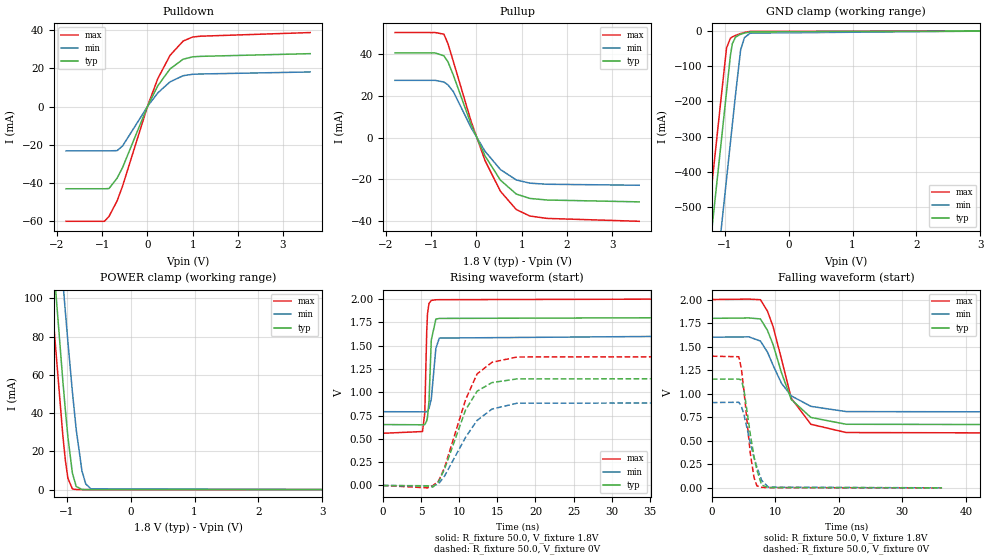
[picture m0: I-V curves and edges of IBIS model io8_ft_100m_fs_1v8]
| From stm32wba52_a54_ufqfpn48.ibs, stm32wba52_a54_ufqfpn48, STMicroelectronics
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[Model]   io8_ft_100m_fs_1v8
Model_type I/O
Polarity   Non-Inverting
Enable   Active-Low
| CAP_THRESHOLD on pad IOFT is "UDTCAPC" :
| Rising=30.0% of vddiom   Falling=70.0% of vddiom
| C_comp min and max val. don't necessarily correlate with the min and max pvt
| but are the smallest and greatest pad capacitance found.
| var   typ   min   max
C_comp   2.20755pF  2.09930pF  2.39591pF
|C_comp_pullup   1.38185pF  1.31775pF  1.46417pF
|C_comp_pulldown   825.70019fF  781.55002fF  931.74609fF
Vinl = 800.0mV
Vinh = 1.0V
Vmeas = 900.0mV   | Reference voltage for timing measurements
Cref  = 50.0pF   | Timing specification test load capacitance value
Rref  = 1.0MOhm   | Timing specification test load resistance value
Vref  = 990.0mV   | Timing specification test load voltage
[Model Spec]
| TIME_THRESHOLD on pin ZIV11 is "CMOS" :
| Rising=50.0% of vdd   Falling=50.0% of vdd
Vinl 702.50000mV 642.50000mV 771.50000mV
Vinh 1.09050V 944.50000mV 1.21950V
| variable   typ   min   max
[Temperature Range] 25.0 140.0 -40.0
| variable   typ   min   max
[Voltage Range] 1.8V 1.6V 2.0V
| variable   typ   min   max
[POWER Clamp Reference] 1.8V 1.6V 2.0V
| variable   typ   min   max
[GND Clamp Reference] 0V 0V 0V
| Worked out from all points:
|   slope of the pulldown table from 0 to 0.27 V, typ, clamps not added: 21.7 ohm
|   slope of the pullup table from 0 to 0.27 V, typ, clamps not added: 22.5 ohm
|   GND clamp passes 1 mA (typ) near -0.51 V on its own axis
|   POWER clamp passes 1 mA (typ) near -0.83 V on its own axis
|   rising waveform, R_fixture 50.0, V_fixture 1.8V: 20-80 % time 322ps typ, 505ps min, 248ps max; typ from 0.654 V to 1.8 V
|   falling waveform, R_fixture 50.0, V_fixture 1.8V: 20-80 % time 4.02ns typ, 4.38ns min, 4.02ns max; typ from 1.8 V to 0.654 V
|   rising waveform, R_fixture 50.0, V_fixture 0V: 20-80 % time 3.25ns typ, 4ns min, 3.39ns max; typ from 0 V to 1.16 V
|   falling waveform, R_fixture 50.0, V_fixture 0V: 20-80 % time 1.6ns typ, 2.02ns min, 1.33ns max; typ from 1.16 V to 0 V
[POWER Clamp]
-1.8V     396.4mA    438.1mA    365.5mA
-1.26V    143.5mA    194.6mA    112.6mA
-1.19V    112.3mA    164.2mA    81.56mA
-1.06V    57.23mA    109.3mA    28.68mA
-1.02V    41.75mA    93.06mA    15.5mA
-980mV    27.6mA     77.28mA    5.935mA
-910mV    8.693mA    51.24mA    382.3uA
-850mV    1.642mA    31.41mA    23.97uA
-760mV    69.41uA    9.714mA    358.6nA
-700mV    7.83uA     2.919mA    21.79nA
-620mV    424.6nA    410.3uA    573.9pA
3.6V      0A         0A         0A
[GND Clamp]
-1.8V     -1.583A    -1.83A     -1.456A
-1.43V    -953.9mA   -1.201A    -826.8mA
-1.24V    -630.9mA   -877.8mA   -503.8mA
-1.05V    -307.9mA   -554.8mA   -180.8mA
-970mV    -171.9mA   -418.8mA   -48.31mA
-910mV    -69.87mA   -316.8mA   -20.91mA
-880mV    -36.5mA    -265.8mA   -17.19mA
-830mV    -17.68mA   -180.8mA   -12.97mA
-750mV    -9.66mA    -53.66mA   -7.697mA
-690mV    -6.479mA   -19.19mA   -4.622mA
-600mV    -3.058mA   -6.478mA   -1.59mA
3.6V      1.281nA    1.39uA     517.2pA
| variable   typ   min   max
[Pullup Reference] 1.8V 1.6V 2.0V
| variable   typ   min   max
[Pulldown Reference] 0V 0V 0V
[Pullup]
-1.8V     40.39mA    27.3mA     50.13mA
-910mV    40.38mA    27.3mA     50.13mA
-720mV    39.03mA    26.51mA    49.35mA
-630mV    36.17mA    25.17mA    44.85mA
-510mV    29.75mA    21.9mA     36.26mA
-120mV    6.338mA    4.782mA    7.854mA
190mV     -8.788mA   -6.58mA    -11.01mA
530mV     -20.35mA   -15.28mA   -25.66mA
880mV     -26.99mA   -20.26mA   -34.39mA
1.18V     -29.09mA   -21.8mA    -37.49mA
1.56V     -29.85mA   -22.32mA   -38.64mA
3.6V      -30.74mA   -22.8mA    -40.02mA
[Pulldown]
-1.8V     -42.97mA   -23.15mA   -59.99mA
-950mV    -42.97mA   -23.15mA   -59.99mA
-850mV    -42.87mA   -23.15mA   -57.45mA
-670mV    -37.41mA   -23.03mA   -49.3mA
-550mV    -31.91mA   -20.61mA   -41.6mA
10mV      539.8uA    356.7uA    722uA
230mV     10.88mA    7.174mA    14.64mA
500mV     19.69mA    12.93mA    26.79mA
790mV     24.78mA    16.15mA    34.26mA
1V        26.02mA    16.89mA    36.38mA
1.18V     26.27mA    17.05mA    36.82mA
3.6V      27.68mA    18.11mA    38.71mA
[Ramp]
dV/dt_r 693.11066mV/3.20118ns 543.26724mV/3.98947ns 838.84424mV/3.36461ns
dV/dt_f 687.69285mV/3.59146ns 484.94098mV/4.15996ns 864.00255mV/3.42462ns
R_load = 50.0
| Removed startup time: 0s 0s 0s  .
| Removed end time: 36.25ns.
[Rising Waveform]
R_fixture   = 50.0
V_fixture   = 1.8V
V_fixture_min = 1.6V
V_fixture_max = 2.0V
0s        653.8mV    791.8mV    560mV
5.2ns     651.3mV    790.6mV    578.8mV
5.5ns     653.3mV    788.1mV    782.7mV
5.75ns    694.7mV    792.7mV    1.649V
5.85ns    732.3mV    799.4mV    1.84V
6.05ns    902.5mV    827.7mV    1.955V
6.35ns    1.561V     928.2mV    1.986V
6.95ns    1.785V     1.472V     1.993V
7.4ns     1.793V     1.582V     1.994V
36.25ns   1.8V       1.6V       2V
| Removed startup time: 0s 0s 0s  .
| Removed end time: 199.25ns.
[Falling Waveform]
R_fixture   = 50.0
V_fixture   = 1.8V
V_fixture_min = 1.6V
V_fixture_max = 2.0V
0s        1.8V       1.6V       2V
5.85ns    1.804V     1.603V     2.004V
7.65ns    1.794V     1.559V     1.998V
8.75ns    1.673V     1.442V     1.877V
9.65ns    1.52V      1.3V       1.711V
10.95ns   1.226V     1.112V     1.371V
12.5ns    938.3mV    976.9mV    951.9mV
15.6ns    747.6mV    865.3mV    675.1mV
21.15ns   675.3mV    809.9mV    587.4mV
199.3ns   653.8mV    791.8mV    560mV
| Removed startup time: 0s 0s 0s  .
| Removed end time: 199.2ns.
[Rising Waveform]
R_fixture   = 50.0
V_fixture   = 0V
V_fixture_min = 0V
V_fixture_max = 0V
0s        4.66nV     680.4nV    3.931nV
5.85ns    -5.875mV   -3.215mV   -25.64mV
6.55ns    -17.15mV   -6.295mV   -1.316mV
7.3ns     38.79mV    16.25mV    47.78mV
8.1ns     178.5mV    103.1mV    195.2mV
10.85ns   812.2mV    518.2mV    922.4mV
12.35ns   1.012V     698.2mV    1.197V
14.3ns    1.104V     820mV      1.322V
17.6ns    1.144V     882.9mV    1.379V
199.2ns   1.155V     905.4mV    1.398V
| Removed startup time: 0s 0s 0s  .
| Removed end time: 36.25ns.
[Falling Waveform]
R_fixture   = 50.0
V_fixture   = 0V
V_fixture_min = 0V
V_fixture_max = 0V
0s        1.155V     905.5mV    1.398V
4.25ns    1.155V     908.9mV    1.392V
4.65ns    1.145V     864.5mV    1.265V
5.05ns    1.041V     780.1mV    1.032V
6.05ns    570.6mV    478.5mV    367.9mV
6.65ns    326.2mV    317.5mV    106.3mV
7.1ns     189.9mV    219mV      21.24mV
7.85ns    29.74mV    78.62mV    5.408mV
8.9ns     3.144mV    7.692mV    2.549mV
36.25ns   741.1nV    624.9nV    2.265uV
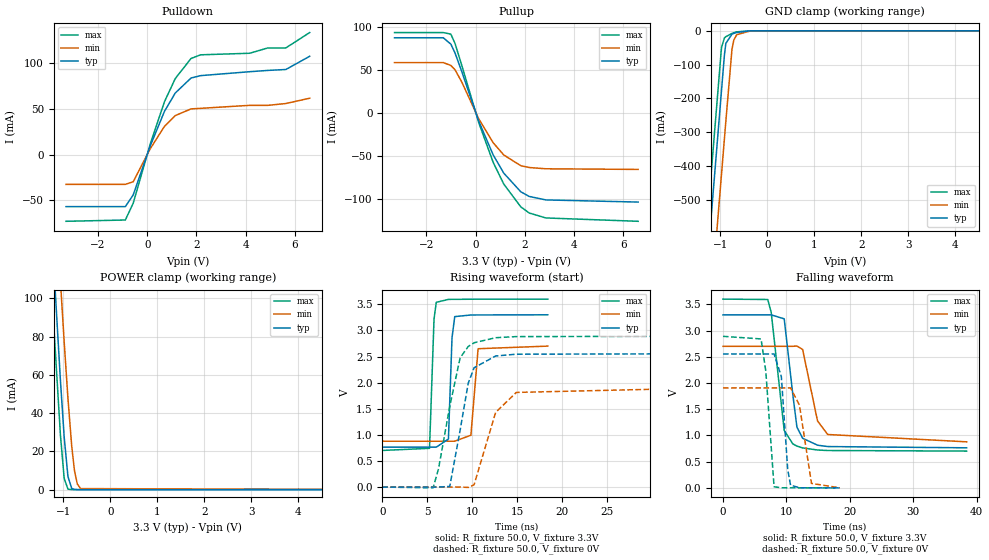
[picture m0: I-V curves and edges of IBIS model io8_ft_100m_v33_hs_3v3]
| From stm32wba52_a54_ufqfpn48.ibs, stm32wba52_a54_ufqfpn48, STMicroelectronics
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[Model]   io8_ft_100m_v33_hs_3v3
Model_type I/O
Polarity   Non-Inverting
Enable   Active-Low
| CAP_THRESHOLD on pad IOFT is "UDTCAPC" :
| Rising=30.0% of vddiom   Falling=70.0% of vddiom
| C_comp min and max val. don't necessarily correlate with the min and max pvt
| but are the smallest and greatest pad capacitance found.
| var   typ   min   max
C_comp   2.72379pF  2.64035pF  2.77560pF
|C_comp_pullup   1.81482pF  1.75600pF  1.84990pF
|C_comp_pulldown   908.97285fF  884.35130fF  925.69520fF
Vinl = 1.35V
Vinh = 1.8V
Vmeas = 1.65V   | Reference voltage for timing measurements
Cref  = 50.0pF   | Timing specification test load capacitance value
Rref  = 1.0MOhm   | Timing specification test load resistance value
Vref  = 1.815V   | Timing specification test load voltage
[Model Spec]
| TIME_THRESHOLD on pin ZIV33M is "CMOS" :
| Rising=50.0% of vddiom   Falling=50.0% of vddiom
Vinl 1.28450V 1.07650V 1.38450V
Vinh 1.79550V 1.49050V 1.94250V
| variable   typ   min   max
[Temperature Range] 25.0 140.0 -40.0
| variable   typ   min   max
[Voltage Range] 3.3V 2.7V 3.6V
| variable   typ   min   max
[POWER Clamp Reference] 3.3V 2.7V 3.6V
| variable   typ   min   max
[GND Clamp Reference] 0V 0V 0V
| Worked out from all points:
|   slope of the pulldown table from 0 to 0.495 V, typ, clamps not added: 14 ohm
|   slope of the pullup table from 0 to 0.495 V, typ, clamps not added: 13.8 ohm
|   GND clamp passes 1 mA (typ) near -0.51 V on its own axis
|   POWER clamp passes 1 mA (typ) near -0.83 V on its own axis
|   rising waveform, R_fixture 50.0, V_fixture 3.3V: 20-80 % time 262ps typ, 340ps min, 238ps max; typ from 0.764 V to 3.3 V
|   falling waveform, R_fixture 50.0, V_fixture 3.3V: 20-80 % time 1.18ns typ, 1.6ns min, 1.55ns max; typ from 3.3 V to 0.764 V
|   rising waveform, R_fixture 50.0, V_fixture 0V: 20-80 % time 1.51ns typ, 2.09ns min, 1.86ns max; typ from 0 V to 2.55 V
|   falling waveform, R_fixture 50.0, V_fixture 0V: 20-80 % time 833ps typ, 1.11ns min, 843ps max; typ from 2.55 V to 0 V
[POWER Clamp]
-3.3V     1.123A     1.139A     1.091A
-1.36V    189.2mA    238.8mA    158.1mA
-1.25V    139mA      190.3mA    108.1mA
-1.18V    107.9mA    159.9mA    77.22mA
-1.06V    57.23mA    109.3mA    28.68mA
-980mV    27.6mA     77.28mA    5.935mA
-900mV    6.895mA    47.74mA    242.8uA
-820mV    594.6uA    22.85mA    5.912uA
-760mV    69.41uA    9.714mA    358.6nA
-700mV    7.83uA     2.919mA    21.86nA
-630mV    611.5nA    529.9uA    954.5pA
6.6V      0A         0A         0A
[GND Clamp]
-3.3V     -4.134A    -4.382A    -4.006A
-1.59V    -1.227A    -1.475A    -1.099A
-1.25V    -648.9mA   -896.7mA   -520.9mA
-980mV    -189.9mA   -437.7mA   -61.92mA
-970mV    -172.9mA   -420.7mA   -48.45mA
-910mV    -70.86mA   -318.7mA   -21.03mA
-880mV    -37.23mA   -267.7mA   -17.31mA
-750mV    -9.908mA   -55.25mA   -7.768mA
-710mV    -7.626mA   -27.41mA   -5.608mA
-650mV    -4.885mA   -11.6mA    -3.058mA
-360mV    -31.22uA   -443.6uA   -1.188uA
6.6V      2.31nA     2.655uA    974.6pA
| variable   typ   min   max
[Pullup Reference] 3.3V 2.7V 3.6V
| variable   typ   min   max
[Pulldown Reference] 0V 0V 0V
[Pullup]
-3.3V     87.4mA     58.48mA    93.44mA
-1.32V    87.4mA     58.48mA    93.44mA
-1.01V    79.96mA    55.17mA    91.59mA
-840mV    69.65mA    50.07mA    80.67mA
-570mV    48.3mA     36.04mA    55.62mA
120mV     -9.566mA   -6.929mA   -11.25mA
710mV     -49.08mA   -34.92mA   -57.81mA
1.14V     -70.33mA   -49.14mA   -83.06mA
1.83V     -91.98mA   -61.62mA   -109.5mA
2.17V     -97.42mA   -63.75mA   -116.7mA
2.85V     -101.5mA   -65.23mA   -122.5mA
6.6V      -104mA     -65.97mA   -126.4mA
[Pulldown]
-3.3V     -56.7mA    -32.4mA    -72.73mA
-890mV    -56.7mA    -32.4mA    -71.32mA
-570mV    -43.94mA   -29.54mA   -52.99mA
120mV     9.474mA    6.407mA    11.48mA
700mV     47.33mA    30.97mA    57.88mA
1.14V     67.41mA    42.74mA    83.2mA
1.78V     83.75mA    50.04mA    105.1mA
2.17V     86.37mA    50.65mA    109.1mA
4.16V     90.65mA    53.91mA    110.8mA
4.9V      92.06mA    53.91mA    116.6mA
5.63V     93.04mA    55.89mA    116.6mA
6.6V      107.5mA    61.71mA    133.4mA
[Ramp]
dV/dt_r 1.53258V/1.50294ns 1.14345V/2.03091ns 1.73411V/1.84246ns
dV/dt_f 1.52158V/1.17992ns 1.09316V/1.53118ns 1.73924V/1.55401ns
R_load = 50.0
| Removed startup time: 0s 0s 0s  .
| Removed end time: 18.4ns.
[Rising Waveform]
R_fixture   = 50.0
V_fixture   = 3.3V
V_fixture_min = 2.7V
V_fixture_max = 3.6V
0s        764mV      878.1mV    701.3mV
5.25ns    764.1mV    878.1mV    742.1mV
5.75ns    764.1mV    878.1mV    3.217V
6ns       764.1mV    878.1mV    3.539V
7.35ns    919.8mV    878.1mV    3.595V
7.75ns    2.86V      878.1mV    3.596V
8.05ns    3.265V     878.1mV    3.596V
9.85ns    3.296V     992.7mV    3.598V
10.65ns   3.297V     2.65V      3.599V
18.4ns    3.3V       2.7V       3.6V
| Removed startup time: 0s 0s 0s  .
| Removed end time: 38.4ns.
[Falling Waveform]
R_fixture   = 50.0
V_fixture   = 3.3V
V_fixture_min = 2.7V
V_fixture_max = 3.6V
0s        3.3V       2.7V       3.6V
7.05ns    3.3V       2.7V       3.593V
7.6ns     3.3V       2.7V       3.347V
9.65ns    3.224V     2.7V       1.096V
11ns      1.785V     2.7V       839.4mV
11.65ns   1.16V      2.706V     796.8mV
12.55ns   946.5mV    2.641V     762mV
14.9ns    814mV      1.276V     722.2mV
16.5ns    788mV      1.018V     712.6mV
38.4ns    764mV      878.1mV    701.3mV
| Removed startup time: 0s 0s 0s  .
| Removed end time: 38.35ns.
[Rising Waveform]
R_fixture   = 50.0
V_fixture   = 0V
V_fixture_min = 0V
V_fixture_max = 0V
0s        20.88nV    574.1nV    33.14nV
5.65ns    5.625uV    585.7nV    -15.38mV
6.25ns    9.505uV    653.9nV    349.3mV
7.5ns     12.34mV    2.897uV    1.546V
8.65ns    1.088V     46.07uV    2.476V
9.55ns    1.988V     -7.138mV   2.692V
10.2ns    2.285V     42.2mV     2.764V
12.6ns    2.511V     1.431V     2.861V
14.9ns    2.545V     1.813V     2.882V
38.35ns   2.554V     1.906V     2.89V
| Removed startup time: 0s 0s 0s  .
| Removed end time: 18.4ns.
[Falling Waveform]
R_fixture   = 50.0
V_fixture   = 0V
V_fixture_min = 0V
V_fixture_max = 0V
0s        2.554V     1.906V     2.89V
6ns       2.554V     1.906V     2.841V
6.75ns    2.554V     1.906V     2.224V
8.05ns    2.554V     1.906V     20.75mV
9.2ns     2.12V      1.906V     2.078mV
10.2ns    350.4mV    1.906V     1.317mV
10.65ns   51.1mV     1.906V     1.141mV
12.05ns   2.086mV    1.578V     815.6uV
13.95ns   1.02mV     84.68mV    515.9uV
18.4ns    291.9uV    1.262mV    146.9uV
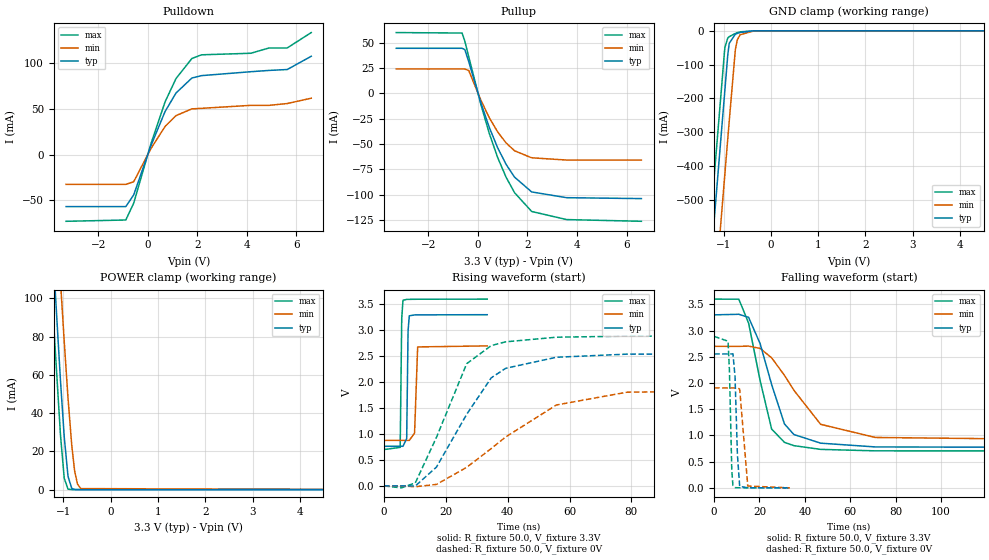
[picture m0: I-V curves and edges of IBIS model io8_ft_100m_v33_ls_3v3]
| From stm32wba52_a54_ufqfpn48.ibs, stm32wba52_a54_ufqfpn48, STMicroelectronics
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[Model]   io8_ft_100m_v33_ls_3v3
Model_type I/O
Polarity   Non-Inverting
Enable   Active-Low
| CAP_THRESHOLD on pad IOFT is "UDTCAPC" :
| Rising=30.0% of vddiom   Falling=70.0% of vddiom
| C_comp min and max val. don't necessarily correlate with the min and max pvt
| but are the smallest and greatest pad capacitance found.
| var   typ   min   max
C_comp   2.72379pF  2.64023pF  2.77562pF
|C_comp_pullup   1.81413pF  1.75530pF  1.84922pF
|C_comp_pulldown   909.66885fF  884.92580fF  926.39520fF
Vinl = 1.35V
Vinh = 1.8V
Vmeas = 1.65V   | Reference voltage for timing measurements
Cref  = 50.0pF   | Timing specification test load capacitance value
Rref  = 1.0MOhm   | Timing specification test load resistance value
Vref  = 1.815V   | Timing specification test load voltage
[Model Spec]
| TIME_THRESHOLD on pin ZIV33M is "CMOS" :
| Rising=50.0% of vddiom   Falling=50.0% of vddiom
Vinl 1.28450V 1.07650V 1.38450V
Vinh 1.79550V 1.49050V 1.94250V
| variable   typ   min   max
[Temperature Range] 25.0 140.0 -40.0
| variable   typ   min   max
[Voltage Range] 3.3V 2.7V 3.6V
| variable   typ   min   max
[POWER Clamp Reference] 3.3V 2.7V 3.6V
| variable   typ   min   max
[GND Clamp Reference] 0V 0V 0V
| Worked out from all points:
|   slope of the pulldown table from 0 to 0.495 V, typ, clamps not added: 14 ohm
|   slope of the pullup table from 0 to 0.495 V, typ, clamps not added: 13.8 ohm
|   GND clamp passes 1 mA (typ) near -0.51 V on its own axis
|   POWER clamp passes 1 mA (typ) near -0.83 V on its own axis
|   rising waveform, R_fixture 50.0, V_fixture 3.3V: 20-80 % time 263ps typ, 346ps min, 236ps max; typ from 0.764 V to 3.3 V
|   falling waveform, R_fixture 50.0, V_fixture 3.3V: 20-80 % time 10.5ns typ, 17.9ns min, 8.53ns max; typ from 3.3 V to 0.764 V
|   rising waveform, R_fixture 50.0, V_fixture 0V: 20-80 % time 15.6ns typ, 27.2ns min, 11.8ns max; typ from 0 V to 2.55 V
|   falling waveform, R_fixture 50.0, V_fixture 0V: 20-80 % time 1.1ns typ, 1.6ns min, 919ps max; typ from 2.55 V to 0 V
[POWER Clamp]
-3.3V     1.123A     1.139A     1.091A
-1.36V    189.2mA    238.8mA    158.1mA
-1.25V    139mA      190.3mA    108.1mA
-1.18V    107.9mA    159.9mA    77.22mA
-1.06V    57.23mA    109.3mA    28.68mA
-980mV    27.6mA     77.28mA    5.935mA
-900mV    6.895mA    47.74mA    242.8uA
-820mV    594.6uA    22.85mA    5.912uA
-760mV    69.41uA    9.714mA    358.6nA
-700mV    7.83uA     2.919mA    21.86nA
-630mV    611.5nA    529.9uA    954.5pA
6.6V      0A         0A         0A
[GND Clamp]
-3.3V     -4.134A    -4.382A    -4.006A
-1.59V    -1.227A    -1.475A    -1.099A
-1.25V    -648.9mA   -896.7mA   -520.9mA
-980mV    -189.9mA   -437.7mA   -61.92mA
-970mV    -172.9mA   -420.7mA   -48.45mA
-910mV    -70.86mA   -318.7mA   -21.03mA
-880mV    -37.23mA   -267.7mA   -17.31mA
-750mV    -9.908mA   -55.25mA   -7.768mA
-710mV    -7.626mA   -27.41mA   -5.608mA
-650mV    -4.885mA   -11.6mA    -3.058mA
-360mV    -31.22uA   -443.6uA   -1.188uA
6.6V      2.31nA     2.655uA    974.6pA
| variable   typ   min   max
[Pullup Reference] 3.3V 2.7V 3.6V
| variable   typ   min   max
[Pulldown Reference] 0V 0V 0V
[Pullup]
-3.3V     44.29mA    23.88mA    59.81mA
-640mV    44.29mA    23.88mA    59.35mA
-530mV    42.99mA    23.88mA    51.44mA
-370mV    31.03mA    22.28mA    35.9mA
120mV     -9.566mA   -6.929mA   -11.25mA
460mV     -33.84mA   -24.28mA   -39.82mA
800mV     -54.04mA   -38.32mA   -63.68mA
1.14V     -70.33mA   -49.14mA   -83.06mA
1.48V     -82.86mA   -56.83mA   -98.19mA
2.17V     -97.42mA   -63.75mA   -116.7mA
3.58V     -103.1mA   -65.97mA   -124.7mA
6.6V      -104mA     -65.97mA   -126.4mA
[Pulldown]
-3.3V     -56.7mA    -32.4mA    -72.73mA
-890mV    -56.7mA    -32.4mA    -71.32mA
-570mV    -43.94mA   -29.54mA   -52.99mA
120mV     9.474mA    6.407mA    11.48mA
700mV     47.33mA    30.97mA    57.88mA
1.14V     67.41mA    42.74mA    83.2mA
1.78V     83.75mA    50.04mA    105.1mA
2.17V     86.37mA    50.65mA    109.1mA
4.16V     90.65mA    53.91mA    110.8mA
4.9V      92.06mA    53.91mA    116.6mA
5.63V     93.04mA    55.89mA    116.6mA
6.6V      107.5mA    61.71mA    133.4mA
[Ramp]
dV/dt_r 1.53259V/15.47369ns 1.14354V/27.02731ns 1.73412V/11.7418ns
dV/dt_f 1.52158V/10.47709ns 1.09315V/17.89446ns 1.73923V/8.40245ns
R_load = 50.0
| Removed startup time: 0s 0s 0s  .
| Removed end time: 33.4ns.
[Rising Waveform]
R_fixture   = 50.0
V_fixture   = 3.3V
V_fixture_min = 2.7V
V_fixture_max = 3.6V
0s        764mV      878.1mV    701.3mV
5.25ns    764.1mV    878.1mV    743.4mV
5.75ns    764.1mV    878.1mV    3.226V
6.15ns    764.1mV    878.1mV    3.578V
7.35ns    913.1mV    878.1mV    3.595V
7.8ns     2.992V     878.1mV    3.596V
8.2ns     3.278V     878.1mV    3.596V
9.9ns     3.296V     1.019V     3.597V
10.9ns    3.297V     2.679V     3.598V
33.4ns    3.3V       2.699V     3.6V
| Removed startup time: 0s 0s 0s  .
| Removed end time: 248.4ns.
[Falling Waveform]
R_fixture   = 50.0
V_fixture   = 3.3V
V_fixture_min = 2.7V
V_fixture_max = 3.6V
0s        3.3V       2.7V       3.6V
10.9ns    3.311V     2.699V     3.599V
15.2ns    3.253V     2.704V     3.145V
20.3ns    2.75V      2.659V     2.044V
25.35ns   1.972V     2.481V     1.122V
31ns      1.22V      2.147V     868.6mV
35.15ns   1.018V     1.863V     805.4mV
46.95ns   852.6mV    1.212V     734.1mV
71ns      780.8mV    961.5mV    706.1mV
248.4ns   764mV      878.1mV    701.3mV
| Removed startup time: 0s 0s 0s  .
| Removed end time: 248.4ns.
[Rising Waveform]
R_fixture   = 50.0
V_fixture   = 0V
V_fixture_min = 0V
V_fixture_max = 0V
0s        20.88nV    574.1nV    33.14nV
5.7ns     7.251uV    588.2nV    -36.76mV
10.15ns   -751.1uV   -14.51mV   59.89mV
17ns      365.1mV    29.91mV    939.3mV
26.75ns   1.38V      358.8mV    2.356V
34.7ns    2.084V     721.4mV    2.705V
39.35ns   2.267V     943.9mV    2.777V
55.75ns   2.48V      1.56V      2.866V
78.6ns    2.54V      1.807V     2.887V
248.4ns   2.554V     1.906V     2.89V
| Removed startup time: 0s 0s 0s  .
| Removed end time: 33.4ns.
[Falling Waveform]
R_fixture   = 50.0
V_fixture   = 0V
V_fixture_min = 0V
V_fixture_max = 0V
0s        2.554V     1.906V     2.89V
6.15ns    2.554V     1.906V     2.797V
6.775ns   2.554V     1.906V     2.229V
7.8ns     2.554V     1.906V     340.3mV
8.3ns     2.558V     1.906V     46.13mV
9.225ns   2.132V     1.906V     4.788mV
10.28ns   636.9mV    1.906V     2.555mV
11.28ns   29.05mV    1.886V     2.112mV
14.85ns   1.782mV    34.65mV    1.452mV
33.4ns    226.8uV    363uV      160.2uV
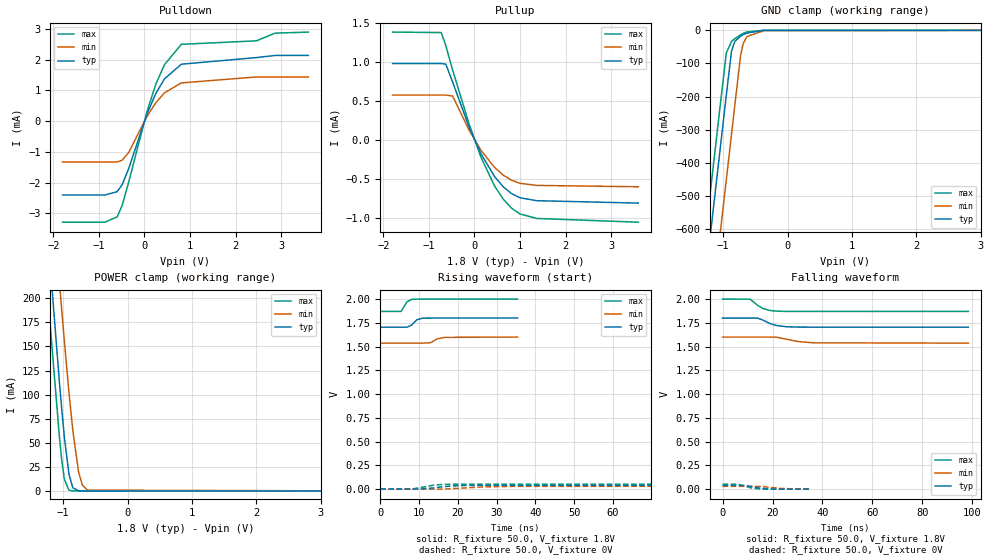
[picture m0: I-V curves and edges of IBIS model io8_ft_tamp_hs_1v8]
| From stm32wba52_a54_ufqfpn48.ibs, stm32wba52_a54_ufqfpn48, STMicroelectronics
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[Model]   io8_ft_tamp_hs_1v8
Model_type I/O
Polarity   Non-Inverting
Enable   Active-Low
| CAP_THRESHOLD on pad IOFT is "UDTCAPC" :
| Rising=30.0% of vddiom   Falling=70.0% of vddiom
| C_comp min and max val. don't necessarily correlate with the min and max pvt
| but are the smallest and greatest pad capacitance found.
| var   typ   min   max
C_comp   6.29605pF  5.93294pF  7.05009pF
|C_comp_pullup   4.08842pF  3.87382pF  4.47715pF
|C_comp_pulldown   2.20764pF  2.05912pF  2.57293pF
Vinl = 800.0mV
Vinh = 1.0V
Vmeas = 900.0mV   | Reference voltage for timing measurements
Cref  = 50.0pF   | Timing specification test load capacitance value
Rref  = 1.0MOhm   | Timing specification test load resistance value
Vref  = 990.0mV   | Timing specification test load voltage
[Model Spec]
| TIME_THRESHOLD on pin ZIV33SW is "CMOS" :
| Rising=50.0% of VDDV33SW   Falling=50.0% of VDDV33SW
Vinl 697.50000mV 636.50000mV 765.50000mV
Vinh 1.08850V 942.50000mV 1.21750V
| variable   typ   min   max
[Temperature Range] 25.0 140.0 -40.0
| variable   typ   min   max
[Voltage Range] 1.8V 1.6V 2.0V
| variable   typ   min   max
[POWER Clamp Reference] 1.8V 1.6V 2.0V
| variable   typ   min   max
[GND Clamp Reference] 0V 0V 0V
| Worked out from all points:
|   slope of the pulldown table from 0 to 0.27 V, typ, clamps not added: 283 ohm
|   slope of the pullup table from 0 to 0.27 V, typ, clamps not added: 855 ohm
|   GND clamp passes 1 mA (typ) near -0.47 V on its own axis
|   POWER clamp passes 1 mA (typ) near -0.81 V on its own axis
|   rising waveform, R_fixture 50.0, V_fixture 1.8V: 20-80 % time 1.33ns typ, 1.84ns min, 1.13ns max; typ from 1.7 V to 1.8 V
|   falling waveform, R_fixture 50.0, V_fixture 1.8V: 20-80 % time 5.31ns typ, 7.46ns min, 4.31ns max; typ from 1.8 V to 1.7 V
[POWER Clamp]
-1.8V     792.8mA    876.2mA    731mA
-1.26V    287mA      389.3mA    225.1mA
-1.19V    224.6mA    328.4mA    163.1mA
-1.06V    114.5mA    218.6mA    57.35mA
-1.02V    83.5mA     186.1mA    30.99mA
-980mV    55.21mA    154.6mA    11.87mA
-910mV    17.39mA    102.5mA    764.6uA
-850mV    3.285mA    62.83mA    47.95uA
-760mV    138.8uA    19.43mA    717.2nA
-700mV    15.66uA    5.838mA    43.61nA
-620mV    848.9nA    820.4uA    1.186nA
3.6V      0A         0A         0A
[GND Clamp]
-1.8V     -1.639A    -1.894A    -1.509A
-1.43V    -1.01A     -1.265A    -879.6mA
-1.24V    -686.9mA   -942.2mA   -556.6mA
-1.05V    -363.9mA   -619.2mA   -233.6mA
-950mV    -193.9mA   -449.2mA   -67.62mA
-870mV    -63.28mA   -313.2mA   -33.62mA
-820mV    -33.62mA   -228.2mA   -25.22mA
-730mV    -17.72mA   -77.21mA   -13.43mA
-690mV    -13.46mA   -40.36mA   -9.392mA
-630mV    -8.329mA   -18.75mA   -4.815mA
-370mV    -86.03uA   -1.078mA   -3.689uA
3.6V      2.71nA     3.15uA     1.142nA
| variable   typ   min   max
[Pullup Reference] 1.8V 1.6V 2.0V
| variable   typ   min   max
[Pulldown Reference] 0V 0V 0V
[Pullup]
-1.8V     980.7uA    575.5uA    1.384mA
-730mV    980.7uA    575.5uA    1.378mA
-630mV    971.8uA    575.5uA    1.21mA
-480mV    742.5uA    562.8uA    895.5uA
-120mV    167uA      126.5uA    207uA
140mV     -175uA     -131uA     -219.2uA
440mV     -469.3uA   -352.1uA   -590.3uA
630mV     -600.6uA   -451uA     -758.9uA
810mV     -687.5uA   -516.3uA   -873.7uA
1V        -742.6uA   -557.2uA   -950.7uA
1.37V     -780.2uA   -583.9uA   -1.008mA
3.6V      -810.9uA   -601.5uA   -1.056mA
[Pulldown]
-1.8V     -2.401mA   -1.328mA   -3.284mA
-870mV    -2.401mA   -1.328mA   -3.284mA
-600mV    -2.291mA   -1.328mA   -3.111mA
-490mV    -2.066mA   -1.268mA   -2.736mA
-350mV    -1.554mA   -1.026mA   -1.996mA
60mV      249uA      165uA      332.9uA
250mV     902.8uA    602.2uA    1.206mA
440mV     1.374mA    920.6uA    1.837mA
810mV     1.85mA     1.242mA    2.495mA
2.46V     2.065mA    1.435mA    2.609mA
2.87V     2.134mA    1.435mA    2.859mA
3.6V      2.134mA    1.435mA    2.893mA
[Ramp]
dV/dt_r 23.80714mV/5.23908ns 17.67119mV/7.98384ns 31.02209mV/4.00819ns
dV/dt_f 57.44949mV/5.2968ns 38.53804mV/7.37335ns 78.08527mV/4.28194ns
R_load = 50.0
| Removed startup time: 0s 0s 0s  .
| Removed end time: 35.4ns.
[Rising Waveform]
R_fixture   = 50.0
V_fixture   = 1.8V
V_fixture_min = 1.6V
V_fixture_max = 2.0V
0s        1.704V     1.536V     1.87V
5.35ns    1.704V     1.536V     1.87V
6.9ns     1.704V     1.536V     1.971V
8.1ns     1.727V     1.536V     1.997V
9.45ns    1.783V     1.536V     1.999V
10.85ns   1.798V     1.536V     2V
13ns      1.8V       1.541V     2V
14.7ns    1.8V       1.581V     2V
16.65ns   1.8V       1.597V     2V
35.4ns    1.8V       1.6V       2V
| Removed startup time: 0s 0s 0s  .
| Removed end time: 98.4ns.
[Falling Waveform]
R_fixture   = 50.0
V_fixture   = 1.8V
V_fixture_min = 1.6V
V_fixture_max = 2.0V
0s        1.8V       1.6V       2V
11ns      1.8V       1.6V       1.999V
14.05ns   1.8V       1.6V       1.934V
16.2ns    1.778V     1.6V       1.9V
18.95ns   1.743V     1.6V       1.88V
21.65ns   1.721V     1.599V     1.873V
25.55ns   1.709V     1.578V     1.87V
30.15ns   1.705V     1.553V     1.87V
36.15ns   1.704V     1.54V      1.87V
98.4ns    1.704V     1.536V     1.87V
| Removed startup time: 0s 0s 0s  .
| Removed end time: 98.35ns.
[Rising Waveform]
R_fixture   = 50.0
V_fixture   = 0V
V_fixture_min = 0V
V_fixture_max = 0V
0s        26.35nV    4.279uV    25.48nV
8.05ns    -1.338mV   4.274uV    179.2uV
10.55ns   132.4uV    4.633uV    16.03mV
13.65ns   11.64mV    -1.205mV   40.16mV
15.45ns   21.17mV    -685.8uV   46.77mV
18ns      31.25mV    2.992mV    50.4mV
21.85ns   37.71mV    11.89mV    51.53mV
26.45ns   39.4mV     22.19mV    51.72mV
34.85ns   39.68mV    28.64mV    51.71mV
98.35ns   39.68mV    29.46mV    51.7mV
| Removed startup time: 0s 0s 0s  .
| Removed end time: 35.4ns.
[Falling Waveform]
R_fixture   = 50.0
V_fixture   = 0V
V_fixture_min = 0V
V_fixture_max = 0V
0s        39.68mV    29.47mV    51.71mV
6.3ns     39.68mV    29.47mV    51.54mV
8.7ns     39.71mV    29.47mV    33.85mV
9.5ns     37.37mV    29.47mV    27.42mV
11.75ns   25.38mV    29.47mV    11.44mV
15.2ns    9.349mV    29.47mV    1.498mV
18.95ns   2.04mV     19.39mV    192.3uV
23.15ns   204.5uV    8.568mV    35.05uV
29.05ns   28.8uV     1.749mV    1.826uV
35.4ns    1.666uV    316.2uV    -320.2nV
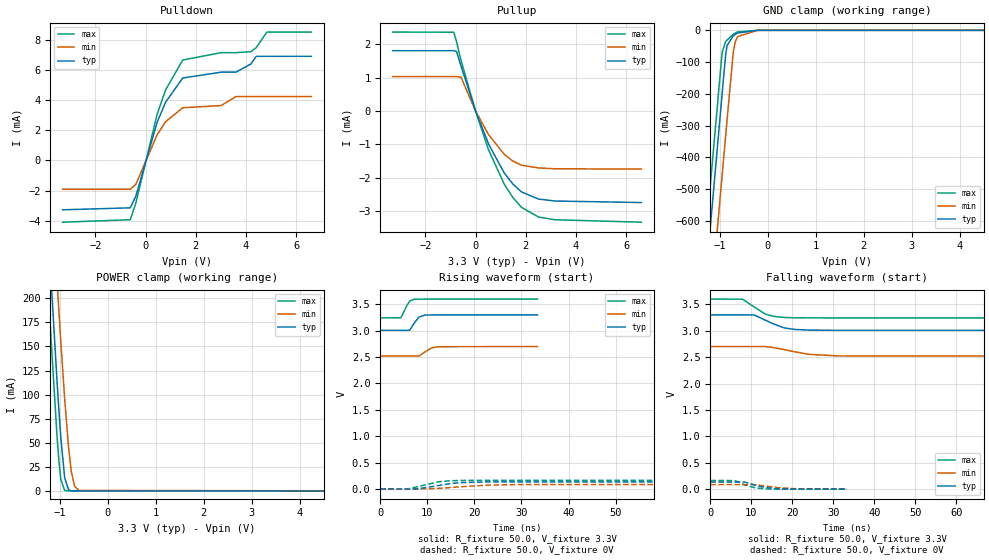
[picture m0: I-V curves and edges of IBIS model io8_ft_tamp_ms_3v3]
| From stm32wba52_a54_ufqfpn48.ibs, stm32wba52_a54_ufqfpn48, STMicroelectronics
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[Model]   io8_ft_tamp_ms_3v3
Model_type I/O
Polarity   Non-Inverting
Enable   Active-Low
| CAP_THRESHOLD on pad IOFT is "UDTCAPC" :
| Rising=30.0% of vddiom   Falling=70.0% of vddiom
| C_comp min and max val. don't necessarily correlate with the min and max pvt
| but are the smallest and greatest pad capacitance found.
| var   typ   min   max
C_comp   8.02922pF  7.67210pF  8.31249pF
|C_comp_pullup   5.44710pF  5.17600pF  5.56509pF
|C_comp_pulldown   2.58211pF  2.49610pF  2.74740pF
Vinl = 1.35V
Vinh = 1.8V
Vmeas = 1.65V   | Reference voltage for timing measurements
Cref  = 50.0pF   | Timing specification test load capacitance value
Rref  = 1.0MOhm   | Timing specification test load resistance value
Vref  = 1.815V   | Timing specification test load voltage
[Model Spec]
| TIME_THRESHOLD on pin ZIV33SW is "CMOS" :
| Rising=50.0% of VDDV33SW   Falling=50.0% of VDDV33SW
Vinl 1.28450V 1.07650V 1.38450V
Vinh 1.79550V 1.49050V 1.94250V
| variable   typ   min   max
[Temperature Range] 25.0 140.0 -40.0
| variable   typ   min   max
[Voltage Range] 3.3V 2.7V 3.6V
| variable   typ   min   max
[POWER Clamp Reference] 3.3V 2.7V 3.6V
| variable   typ   min   max
[GND Clamp Reference] 0V 0V 0V
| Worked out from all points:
|   slope of the pulldown table from 0 to 0.495 V, typ, clamps not added: 186 ohm
|   slope of the pullup table from 0 to 0.495 V, typ, clamps not added: 521 ohm
|   GND clamp passes 1 mA (typ) near -0.47 V on its own axis
|   POWER clamp passes 1 mA (typ) near -0.81 V on its own axis
|   rising waveform, R_fixture 50.0, V_fixture 3.3V: 20-80 % time 1.28ns typ, 1.63ns min, 1.14ns max; typ from 3.01 V to 3.3 V
|   falling waveform, R_fixture 50.0, V_fixture 3.3V: 20-80 % time 5.12ns typ, 7.21ns min, 4.33ns max; typ from 3.3 V to 3.01 V
|   rising waveform, R_fixture 50.0, V_fixture 0V: 20-80 % time 5.57ns typ, 8.32ns min, 4.56ns max; typ from 0 V to 0.135 V
|   falling waveform, R_fixture 50.0, V_fixture 0V: 20-80 % time 4.09ns typ, 5.72ns min, 3.47ns max; typ from 0.135 V to 0 V
[POWER Clamp]
-3.3V     2.246A     2.279A     2.182A
-1.26V    287mA      389.3mA    225.1mA
-1.19V    224.6mA    328.4mA    163.1mA
-1.06V    114.5mA    218.6mA    57.35mA
-1.02V    83.5mA     186.1mA    30.99mA
-980mV    55.21mA    154.6mA    11.87mA
-900mV    13.79mA    95.47mA    485.6uA
-820mV    1.189mA    45.7mA     11.82uA
-760mV    138.8uA    19.43mA    717.3nA
-690mV    10.88uA    4.64mA     27.56nA
-600mV    410.2nA    489.5uA    725pA
6.6V      0A         0A         0A
[GND Clamp]
-3.3V     -4.191A    -4.447A    -4.059A
-1.59V    -1.284A    -1.54A     -1.152A
-1.25V    -705.7mA   -962.2mA   -574mA
-960mV    -212.7mA   -469.2mA   -81mA
-950mV    -195.7mA   -452.2mA   -68.07mA
-880mV    -77.2mA    -333.2mA   -36.04mA
-850mV    -48.09mA   -282.2mA   -30.39mA
-720mV    -17.06mA   -67.51mA   -12.51mA
-680mV    -12.85mA   -36.48mA   -8.6mA
-630mV    -8.529mA   -19.6mA    -4.86mA
-220mV    -490.4nA   -42.83uA   -18.74nA
6.6V      5.835nA    6.044uA    3.958nA
| variable   typ   min   max
[Pullup Reference] 3.3V 2.7V 3.6V
| variable   typ   min   max
[Pulldown Reference] 0V 0V 0V
[Pullup]
-3.3V     1.809mA    1.035mA    2.367mA
-870mV    1.809mA    1.035mA    2.364mA
-760mV    1.789mA    1.035mA    2.086mA
-580mV    1.353mA    1.013mA    1.518mA
0V        940fA      1.883nA    0A
520mV     -992.7uA   -711.1uA   -1.168mA
1.14V     -1.853mA   -1.295mA   -2.188mA
1.48V     -2.183mA   -1.497mA   -2.587mA
1.83V     -2.424mA   -1.624mA   -2.886mA
2.51V     -2.639mA   -1.705mA   -3.178mA
3.17V     -2.697mA   -1.73mA    -3.259mA
6.6V      -2.742mA   -1.738mA   -3.331mA
[Pulldown]
-3.3V     -3.274mA   -1.917mA   -4.095mA
-610mV    -3.144mA   -1.917mA   -3.932mA
-390mV    -2.378mA   -1.591mA   -2.836mA
460mV     2.524mA    1.696mA    3.053mA
800mV     3.862mA    2.563mA    4.678mA
1.48V     5.456mA    3.486mA    6.647mA
3.01V     5.842mA    3.632mA    7.136mA
3.6V      5.844mA    4.228mA    7.136mA
4.19V     6.383mA    4.228mA    7.196mA
4.41V     6.889mA    4.228mA    7.475mA
4.83V     6.894mA    4.228mA    8.498mA
6.6V      6.894mA    4.228mA    8.498mA
[Ramp]
dV/dt_r 80.90882mV/5.53159ns 51.28957mV/8.26573ns 98.35312mV/4.53656ns
dV/dt_f 175.2925mV/5.12305ns 108.33099mV/7.17062ns 214.11117mV/4.31921ns
R_load = 50.0
| Removed startup time: 0s 0s 0s  .
| Removed end time: 33.4ns.
[Rising Waveform]
R_fixture   = 50.0
V_fixture   = 3.3V
V_fixture_min = 2.7V
V_fixture_max = 3.6V
0s        3.008V     2.519V     3.243V
4.4ns     3.008V     2.519V     3.245V
5.65ns    3.008V     2.519V     3.478V
6.25ns    3.009V     2.519V     3.561V
7.05ns    3.122V     2.519V     3.595V
8.2ns     3.259V     2.519V     3.599V
9.5ns     3.297V     2.598V     3.599V
10.9ns    3.299V     2.674V     3.6V
12.3ns    3.3V       2.697V     3.6V
33.4ns    3.3V       2.7V       3.6V
| Removed startup time: 0s 0s 0s  .
| Removed end time: 98.4ns.
[Falling Waveform]
R_fixture   = 50.0
V_fixture   = 3.3V
V_fixture_min = 2.7V
V_fixture_max = 3.6V
0s        3.3V       2.7V       3.6V
7.85ns    3.3V       2.7V       3.598V
10.75ns   3.298V     2.7V       3.448V
13.4ns    3.201V     2.7V       3.317V
15.3ns    3.134V     2.683V     3.274V
18ns      3.054V     2.643V     3.252V
20.55ns   3.025V     2.602V     3.246V
24.1ns    3.012V     2.553V     3.244V
31.15ns   3.008V     2.524V     3.243V
98.4ns    3.008V     2.519V     3.243V
| Removed startup time: 0s 0s 0s  .
| Removed end time: 98.35ns.
[Rising Waveform]
R_fixture   = 50.0
V_fixture   = 0V
V_fixture_min = 0V
V_fixture_max = 0V
0s        162.8nV    4.5uV      290.6nV
5ns       593.5nV    4.496uV    -3.881mV
6ns       54.81uV    4.562uV    4.037mV
8.05ns    3.28mV     30.96uV    45.29mV
12.45ns   67.11mV    11.15mV    136.8mV
14.8ns    101.6mV    26.16mV    155.1mV
17.15ns   120.8mV    41.68mV    161.3mV
22.5ns    133.4mV    71.49mV    163.8mV
29.05ns   134.7mV    83.14mV    163.9mV
98.35ns   134.8mV    85.49mV    163.9mV
| Removed startup time: 0s 0s 0s  .
| Removed end time: 33.35ns.
[Falling Waveform]
R_fixture   = 50.0
V_fixture   = 0V
V_fixture_min = 0V
V_fixture_max = 0V
0s        134.9mV    85.5mV     163.9mV
5.9ns     134.9mV    85.5mV     162.7mV
7ns       134.9mV    85.5mV     134.4mV
8.2ns     134.9mV    85.5mV     87.67mV
9.45ns    113.4mV    85.5mV     53.23mV
11.15ns   67.62mV    85.04mV    24.48mV
13.4ns    31.01mV    58.88mV    4.025mV
17.05ns   3.49mV     24.77mV    211.5uV
21.15ns   180.5uV    6.55mV     29.21uV
33.35ns   912.5nV    31.6uV     828.6nV
